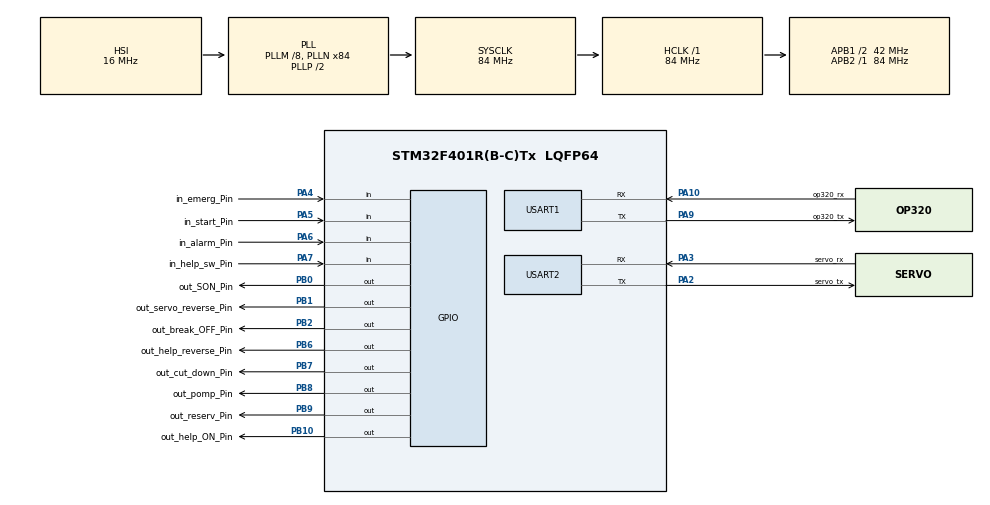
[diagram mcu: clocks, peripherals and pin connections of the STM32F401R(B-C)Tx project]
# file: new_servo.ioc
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Dma.Request0=USART1_RX
Dma.Request1=USART1_TX
Dma.USART1_RX.0.Direction=DMA_PERIPH_TO_MEMORY
Dma.USART1_RX.0.FIFOMode=DMA_FIFOMODE_DISABLE
Dma.USART1_RX.0.Instance=DMA2_Stream2
Dma.USART1_RX.0.MemDataAlignment=DMA_MDATAALIGN_BYTE
Dma.USART1_RX.0.MemInc=DMA_MINC_ENABLE
Dma.USART1_RX.0.Mode=DMA_NORMAL
Dma.USART1_RX.0.PeriphDataAlignment=DMA_PDATAALIGN_BYTE
Dma.USART1_RX.0.PeriphInc=DMA_PINC_DISABLE
Dma.USART1_RX.0.Priority=DMA_PRIORITY_LOW
Dma.USART1_TX.1.Direction=DMA_MEMORY_TO_PERIPH
Dma.USART1_TX.1.FIFOMode=DMA_FIFOMODE_DISABLE
Dma.USART1_TX.1.Instance=DMA2_Stream7
Dma.USART1_TX.1.MemDataAlignment=DMA_MDATAALIGN_BYTE
Dma.USART1_TX.1.MemInc=DMA_MINC_ENABLE
Dma.USART1_TX.1.Mode=DMA_NORMAL
Dma.USART1_TX.1.PeriphDataAlignment=DMA_PDATAALIGN_BYTE
Dma.USART1_TX.1.PeriphInc=DMA_PINC_DISABLE
Dma.USART1_TX.1.Priority=DMA_PRIORITY_LOW
FREERTOS.INCLUDE_uxTaskPriorityGet=1
FREERTOS.INCLUDE_vTaskDelete=1
FREERTOS.INCLUDE_vTaskPrioritySet=1
FREERTOS.Tasks01=OP320TaskFunc,24,1024,OP320Task,Default,NULL,Dynamic,NULL,NULL;ControlTaskName,24,1024,ControlTask,Default,NULL,Dynamic,NULL,NULL;ServoTaskName,24,1024,ServoTask,Default,NULL,Dynamic,NULL,NULL
FREERTOS.configMINIMAL_STACK_SIZE=256
FREERTOS.configTOTAL_HEAP_SIZE=20000
FREERTOS.configUSE_NEWLIB_REENTRANT=1
Mcu.Family=STM32F4
Mcu.Name=STM32F401R(B-C)Tx
Mcu.Package=LQFP64
NVIC.DMA2_Stream2_IRQn=true\:5\:0\:false\:false\:true\:true\:false\:true\:true
NVIC.DMA2_Stream7_IRQn=true\:5\:0\:false\:false\:true\:true\:false\:true\:true
NVIC.PriorityGroup=NVIC_PRIORITYGROUP_4
NVIC.TIM1_UP_TIM10_IRQn=true\:15\:0\:false\:false\:true\:false\:false\:true\:true
NVIC.TimeBase=TIM1_UP_TIM10_IRQn
NVIC.TimeBaseIP=TIM1
NVIC.USART1_IRQn=true\:5\:0\:false\:false\:true\:true\:true\:true\:true
NVIC.USART2_IRQn=true\:5\:0\:false\:false\:true\:true\:true\:true\:true
PA10.GPIO_Label=op320_rx
PA10.Mode=Asynchronous
PA10.Signal=USART1_RX
PA2.GPIO_Label=servo_tx
PA2.Mode=Asynchronous
PA2.Signal=USART2_TX
PA3.GPIO_Label=servo_rx
PA3.Mode=Asynchronous
PA3.Signal=USART2_RX
PA4.GPIO_Label=in_emerg_Pin
PA4.Signal=GPIO_Input
PA5.GPIO_Label=in_start_Pin
PA5.Signal=GPIO_Input
PA6.GPIO_Label=in_alarm_Pin
PA6.Signal=GPIO_Input
PA7.GPIO_Label=in_help_sw_Pin
PA7.Signal=GPIO_Input
PA9.GPIO_Label=op320_tx
PA9.Mode=Asynchronous
PA9.Signal=USART1_TX
PB0.GPIO_Label=out_SON_Pin
PB0.GPIO_PuPd=GPIO_PULLDOWN
PB0.Signal=GPIO_Output
PB1.GPIO_Label=out_servo_reverse_Pin
PB1.GPIO_PuPd=GPIO_NOPULL
PB1.Signal=GPIO_Output
PB10.GPIO_Label=out_help_ON_Pin
PB10.Signal=GPIO_Output
PB2.GPIO_Label=out_break_OFF_Pin
PB2.GPIO_PuPd=GPIO_NOPULL
PB2.Signal=GPIO_Output
PB6.GPIO_Label=out_help_reverse_Pin
PB6.Signal=GPIO_Output
PB7.GPIO_Label=out_cut_down_Pin
PB7.Signal=GPIO_Output
PB8.GPIO_Label=out_pomp_Pin
PB8.Signal=GPIO_Output
PB9.GPIO_Label=out_reserv_Pin
PB9.Signal=GPIO_Output
PC14-OSC32_IN.Mode=LSE-External-Oscillator
PC14-OSC32_IN.Signal=RCC_OSC32_IN
PC15-OSC32_OUT.Mode=LSE-External-Oscillator
PC15-OSC32_OUT.Signal=RCC_OSC32_OUT
PH0\ -\ OSC_IN.Mode=HSE-External-Oscillator
PH0\ -\ OSC_IN.Signal=RCC_OSC_IN
PH1\ -\ OSC_OUT.Mode=HSE-External-Oscillator
PH1\ -\ OSC_OUT.Signal=RCC_OSC_OUT
ProjectManager.HeapSize=0x200
ProjectManager.StackSize=0x400
ProjectManager.TargetToolchain=STM32CubeIDE
RCC.48MHZClocksFreq_Value=42000000
RCC.AHBFreq_Value=84000000
RCC.APB1CLKDivider=RCC_HCLK_DIV2
RCC.APB1Freq_Value=42000000
RCC.APB1TimFreq_Value=84000000
RCC.APB2Freq_Value=84000000
RCC.APB2TimFreq_Value=84000000
RCC.CortexFreq_Value=84000000
RCC.HCLKFreq_Value=84000000
RCC.HSE_VALUE=25000000
RCC.HSI_VALUE=16000000
RCC.PLLM=8
RCC.PLLN=84
RCC.SYSCLKFreq_VALUE=84000000
RCC.SYSCLKSource=RCC_SYSCLKSOURCE_PLLCLK
RCC.VCOOutputFreq_Value=168000000
USART1.VirtualMode=VM_ASYNC
USART2.VirtualMode=VM_ASYNC
VP_FREERTOS_VS_CMSIS_V2.Mode=CMSIS_V2
VP_SYS_VS_tim1.Mode=TIM1
board=custom

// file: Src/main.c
 #include "main.h"
#include "cmsis_os.h"

/* USER CODE BEGIN Includes */
#include "servo_control.h"
#include "servo_flash.h"
#include "servo_tools.h"
#include "servo_amplifier.h"
#include "op320.h"
#include "math.h"
/* USER CODE END Includes */

/* USER CODE BEGIN PM */
#define DELAY_HELP 8
/* USER CODE END PM */

UART_HandleTypeDef huart1;
UART_HandleTypeDef huart2;
DMA_HandleTypeDef hdma_usart1_rx;
DMA_HandleTypeDef hdma_usart1_tx;

/* Definitions for OP320TaskFunc */
const osThreadAttr_t OP320TaskFunc_attributes = {
  .name = "",
  .stack_size = 1024 * 4,
  .priority = (osPriority_t) osPriorityNormal,
};
/* Definitions for ReadServoResponse */
const osThreadAttr_t ReadServoResponse_attributes = {
  .name = "",
  .stack_size = 1024 * 4,
  .priority = (osPriority_t) osPriorityNormal2,
};
/* Definitions for Servo */
const osThreadAttr_t Servo_attributes = {
  .name = "",
  .stack_size = 512 * 4,
  .priority = (osPriority_t) osPriorityNormal1,
};

void SystemClock_Config(void);
static void MX_GPIO_Init(void);
static void MX_DMA_Init(void);
static void MX_USART1_UART_Init(void);
static void MX_USART2_UART_Init(void);
void OP320Task(void *argument);
void ReadServoResponseTask(void *argument);
void ServoTask(void *argument);

int main(void)
{

  /* MCU Configuration--------------------------------------------------------*/

  /* Reset of all peripherals, Initializes the Flash interface and the Systick. */
  HAL_Init();

  /* Configure the system clock */
  SystemClock_Config();

  /* Initialize all configured peripherals */
  MX_GPIO_Init();
  MX_DMA_Init();
  MX_USART1_UART_Init();
  MX_USART2_UART_Init();
  /* USER CODE BEGIN 2 */
  readFlash( ( uint8_t *)&servoParams, sizeof( servoParams ) );

  /* USER CODE END 2 */

  /* Init scheduler */
  osKernelInitialize();

  /* Create the thread(s) */
  /* creation of OP320TaskFunc */
  if( osThreadNew(OP320Task, NULL, &OP320TaskFunc_attributes) == NULL
		  || osThreadNew(ReadServoResponseTask, NULL, &ReadServoResponse_attributes) == NULL
		  ||  osThreadNew(ServoTask, NULL, &Servo_attributes) == NULL )
	  Error_Handler();

  /* USER CODE BEGIN RTOS_EVENTS */

	initServo();
	initOP320();
  /* USER CODE END RTOS_EVENTS */

  /* Start scheduler */
  osKernelStart();

  /* We should never get here as control is now taken by the scheduler */
  /* Infinite loop */
  while (1)
  {

  }
}

void SystemClock_Config(void)
{
  RCC_OscInitTypeDef RCC_OscInitStruct = {0};
  RCC_ClkInitTypeDef RCC_ClkInitStruct = {0};

  /** Configure the main internal regulator output voltage
  */
  __HAL_RCC_PWR_CLK_ENABLE();
  __HAL_PWR_VOLTAGESCALING_CONFIG(PWR_REGULATOR_VOLTAGE_SCALE2);

  /** Initializes the RCC Oscillators according to the specified parameters
  * in the RCC_OscInitTypeDef structure.
  */
  RCC_OscInitStruct.OscillatorType = RCC_OSCILLATORTYPE_HSI;
  RCC_OscInitStruct.HSIState = RCC_HSI_ON;
  RCC_OscInitStruct.HSICalibrationValue = RCC_HSICALIBRATION_DEFAULT;
  RCC_OscInitStruct.PLL.PLLState = RCC_PLL_ON;
  RCC_OscInitStruct.PLL.PLLSource = RCC_PLLSOURCE_HSI;
  RCC_OscInitStruct.PLL.PLLM = 8;
  RCC_OscInitStruct.PLL.PLLN = 84;
  RCC_OscInitStruct.PLL.PLLP = RCC_PLLP_DIV2;
  RCC_OscInitStruct.PLL.PLLQ = 4;
  if (HAL_RCC_OscConfig(&RCC_OscInitStruct) != HAL_OK)
  {
    Error_Handler();
  }

  /** Initializes the CPU, AHB and APB buses clocks
  */
  RCC_ClkInitStruct.ClockType = RCC_CLOCKTYPE_HCLK|RCC_CLOCKTYPE_SYSCLK
                              |RCC_CLOCKTYPE_PCLK1|RCC_CLOCKTYPE_PCLK2;
  RCC_ClkInitStruct.SYSCLKSource = RCC_SYSCLKSOURCE_PLLCLK;
  RCC_ClkInitStruct.AHBCLKDivider = RCC_SYSCLK_DIV1;
  RCC_ClkInitStruct.APB1CLKDivider = RCC_HCLK_DIV2;
  RCC_ClkInitStruct.APB2CLKDivider = RCC_HCLK_DIV1;

  if (HAL_RCC_ClockConfig(&RCC_ClkInitStruct, FLASH_LATENCY_2) != HAL_OK)
  {
    Error_Handler();
  }
}

static void MX_USART1_UART_Init(void)
{

  huart1.Instance = USART1;
  huart1.Init.BaudRate = 115200;
  huart1.Init.WordLength = UART_WORDLENGTH_8B;
  huart1.Init.StopBits = UART_STOPBITS_1;
  huart1.Init.Parity = UART_PARITY_NONE;
  huart1.Init.Mode = UART_MODE_TX_RX;
  huart1.Init.HwFlowCtl = UART_HWCONTROL_NONE;
  huart1.Init.OverSampling = UART_OVERSAMPLING_16;
  if (HAL_UART_Init(&huart1) != HAL_OK)
  {
    Error_Handler();
  }

}

static void MX_USART2_UART_Init(void)
{

	huart2.Instance = USART2;
	huart2.Init.BaudRate = 38400;
	huart2.Init.WordLength = UART_WORDLENGTH_9B;
	huart2.Init.StopBits = UART_STOPBITS_1;
	huart2.Init.Parity = UART_PARITY_EVEN;
	huart2.Init.Mode = UART_MODE_TX_RX;
	huart2.Init.HwFlowCtl = UART_HWCONTROL_NONE;
	huart2.Init.OverSampling = UART_OVERSAMPLING_16;
  if (HAL_UART_Init(&huart2) != HAL_OK)
  {
    Error_Handler();
  }
}

static void MX_DMA_Init(void)
{

  /* DMA controller clock enable */
  __HAL_RCC_DMA2_CLK_ENABLE();

  /* DMA interrupt init */
  /* DMA2_Stream2_IRQn interrupt configuration */
  HAL_NVIC_SetPriority(DMA2_Stream2_IRQn, 5, 0);
  HAL_NVIC_EnableIRQ(DMA2_Stream2_IRQn);
  /* DMA2_Stream7_IRQn interrupt configuration */
  HAL_NVIC_SetPriority(DMA2_Stream7_IRQn, 5, 0);
  HAL_NVIC_EnableIRQ(DMA2_Stream7_IRQn);

}

static void MX_GPIO_Init(void)
{
  GPIO_InitTypeDef GPIO_InitStruct = {0};

  /* GPIO Ports Clock Enable */
  __HAL_RCC_GPIOC_CLK_ENABLE();
  __HAL_RCC_GPIOH_CLK_ENABLE();
  __HAL_RCC_GPIOA_CLK_ENABLE();
  __HAL_RCC_GPIOB_CLK_ENABLE();

  /*Configure GPIO pin Output Level */
  HAL_GPIO_WritePin(GPIOB, out_cut_act_Pin|out_fix_act_Pin|out_help_ON_Pin
                          |out_help_reverse_Pin, GPIO_PIN_RESET);
  HAL_GPIO_WritePin(debug_GPIO_Port, debug_Pin, GPIO_PIN_SET);

  GPIO_InitStruct.Pin = debug_Pin;
  GPIO_InitStruct.Mode = GPIO_MODE_OUTPUT_PP;
  GPIO_InitStruct.Pull = GPIO_PULLDOWN;
  HAL_GPIO_Init(debug_GPIO_Port, &GPIO_InitStruct);

  GPIO_InitStruct.Pin = in_pomp_Pin;
  GPIO_InitStruct.Mode = GPIO_MODE_INPUT;
  GPIO_InitStruct.Pull = GPIO_NOPULL;
  HAL_GPIO_Init(in_pomp_Port, &GPIO_InitStruct);

  /*Configure GPIO pins : in_emerg_Pin in_start_Pin in_alarm_Pin in_help_sw_Pin */
  GPIO_InitStruct.Pin = in_emerg_Pin|in_start_Pin|in_help_sw_Pin;
  GPIO_InitStruct.Mode = GPIO_MODE_INPUT;
  GPIO_InitStruct.Pull = GPIO_NOPULL;
  HAL_GPIO_Init(GPIOB, &GPIO_InitStruct);

  /*Configure GPIO pins : out_cut_act_Pin out_fix_act_Pin out_help_ON_Pin out_help_reverse_Pin
                           out_cut_act_Pin in_pomp_Pin out_fix_up_Pin */
  GPIO_InitStruct.Pin = out_cut_act_Pin|out_fix_act_Pin|out_help_ON_Pin|out_help_reverse_Pin
                          |out_pneumatic_act_Pin|out_led_Pin;
  GPIO_InitStruct.Mode = GPIO_MODE_OUTPUT_PP;
  GPIO_InitStruct.Pull = GPIO_PULLDOWN;
  GPIO_InitStruct.Speed = GPIO_SPEED_FREQ_LOW;
  HAL_GPIO_Init(GPIOB, &GPIO_InitStruct);

}

void OP320Task(void *argument)
{
  /* USER CODE BEGIN 5 */
  /* Infinite loop */
	osDelay( DELAY_START_TASK );
	for(;;){
		 osDelay( DELAY_READ_BUT );
		 readButton();
		 updateData();
	}
  /* USER CODE END 5 */
}

void ReadServoResponseTask(void *argument)
{
  /* USER CODE BEGIN ReadServoResponseTask */
  /* Infinite loop */
	ServoRXMessage rxMes;
	for(;;)
	{
		osMessageQueueGet( rxMesQueue, &rxMes, NULL, osWaitForever );
		if( isResponseOk( rxMes.resp ) ){
			if( rxMes.requestType == GET_DATA ){
				switch( rxMes.dataType ){
					case ALARM_DATA:
					{
						updateAlarmStatus( rxMes.data );
						break;
					}
					case PARAM_DATA:
					{
						reg_param_val = (uint16_t) rxMes.data;
						break;
					}
					case INFO_DATA:
					{
						if( isRun() ){
							continueServo( rxMes.data );
						}
						break;
					}
					default:
					{
						  break;
					}
				}
			}
		} else if( isModeJog() ){
			updateAlarmStatus( rxMes.resp );
		}
	}

  /* USER CODE END ReadServoResponseTask */
}

void ServoTask(void *argument)
{
  /* USER CODE BEGIN ServoTask */
  /* Infinite loop */
	bool press_but, lock = false, activate = false;
	int c = 0, helpc = 0, cp = 0;
	osDelay( DELAY_START_TASK );
	setParam( 0, 1 );
	blockIO( BLOCK_DI_AI );
	for(;;)
	{
	osDelay( 350 );

	// ---------------- emergency
	if( !isEmergOk() ){
		updateAlarmStatus( AL_E6_EMERG );
	// ---------------- alarm
	} else if( reg_mode == MODE_ALARM ){
		if( !alarm ){
			updateAlarmStatus( AL_OK );
		} else if( isTxQueueEmpty() ){
			getAlarm();
			osDelay( 500 );
		}
	// -------------------normal mode
	} else {

		// button trigger
		press_but = isPressBut();
		if( press_but ){
			if( !lock ){
				activate = true;
				lock = true;
			}
		} else if( lock ) {
			lock = false;
		}

		// select operation
		switch( reg_mode ){
			case MODE_CUTTING:
			{
				if( activate ){
					operation();
				}
				break;
			}
			case MODE_WORK:
			{
				if( activate ){
					setHelp( false );
					MRJ2S_pause();
					osDelay( 200 );
				} else {
					setHelp( isHelpSwitch() );
					if( isTxQueueEmpty() ){
						getFeedbackImp();
						osDelay( 100 );
					}
				}
				break;
			}
			case MODE_HELP_REVERSE:
			case MODE_HELP_DIRECT:
			{
				setHelp( press_but );
				break;
			}
			case MODE_JOG_DIRECT:
			{
				if( press_but ){
					cp = 0;
					if( isTxQueueEmpty() ){
						getFeedbackImp();
						osDelay( 200 );
					}
					setHelp( isHelpSwitch() );
				} else if(cp < 1) {
					cp++;
				} else {
					MRJ2S_pause();
					osDelay( 100 );
					cp = 0;
				}
				break;
			}
			case MODE_JOG_REVERSE:
			{
				if( press_but ){
					cp = 0;
					if( isTxQueueEmpty() ){
						getFeedbackImp();
						osDelay( 100 );
						if( helpc < DELAY_HELP ){
							helpc += 1;
						} else {
							helpc = 0;
							toggleHelp();
						}
					}
				} else if( cp < 1 ) {
					cp++;
				} else {
					MRJ2S_pause();
					cp = 0;
				}
				break;
			}
			case MODE_PAUSA:
			{
				if( activate ){
					MRJ2S_continue();
				}
				break;
			}
			default: break;
		}

		//  blink
		if( reg_mode == MODE_PAUSA
				|| reg_mode == MODE_CUTTING
				|| reg_mode == MODE_HELP_DIRECT
				|| reg_mode == MODE_HELP_REVERSE ){
			 if( c < 3 ){
				c++;
			} else {
				c = 0;
				setLed( !isLed() );
			}
		}

		if( activate ){
			activate = false;
		}

	}
	}
  /* USER CODE END ServoTask */
}

void HAL_TIM_PeriodElapsedCallback(TIM_HandleTypeDef *htim)
{
  if (htim->Instance == TIM1) {
    HAL_IncTick();
  }
}

void Error_Handler(void)
{
  /* USER CODE BEGIN Error_Handler_Debug */
  /* User can add his own implementation to report the HAL error return state */
	__NVIC_SystemReset();
  while (1)
  {
  }
  /* USER CODE END Error_Handler_Debug */
}
